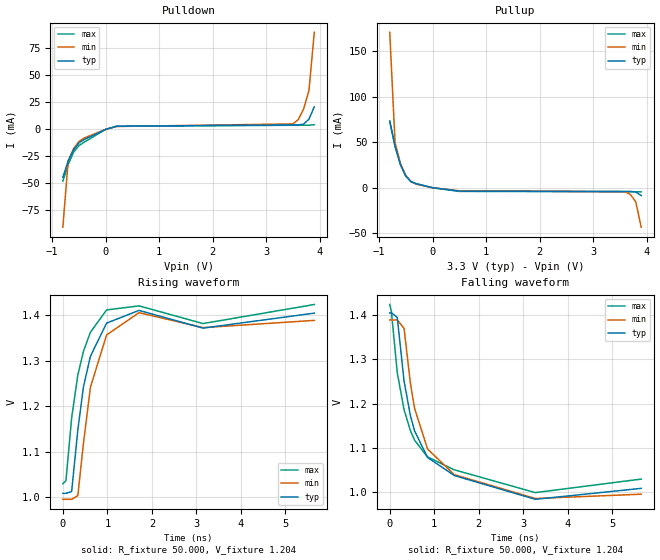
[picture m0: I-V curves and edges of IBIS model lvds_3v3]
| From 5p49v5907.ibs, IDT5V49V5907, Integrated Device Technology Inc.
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[Model]   lvds_3v3
Model_type   Output
Polarity   Non-Inverting
|   typ   min   max
C_comp   2pF   1.5pF   2.5pF
Vmeas = 1.204V
Rref = 50
Cref = 0
Vref = 1.204V
|   typ   min   max
[Voltage range]   3.3V   3.135V   3.465V
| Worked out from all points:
|   slope of the pulldown table from 0 to 0.495 V, typ, clamps not added: 133 ohm
|   slope of the pullup table from 0 to 0.495 V, typ, clamps not added: 133 ohm
|   rising waveform, R_fixture 50.000, V_fixture 1.204: 20-80 % time 395ps typ, 362ps min, 409ps max; typ from 1.01 V to 1.41 V
|   falling waveform, R_fixture 50.000, V_fixture 1.204: 20-80 % time 549ps typ, 612ps min, 518ps max; typ from 1.41 V to 1.01 V
[Pulldown]
|Voltage   I (typ)   I (min)   I (max)
|Note, modeling breaks down at 250mA and above.  This is well beyond the functional   |
|operating range of the device.  Should this scenario occur, catastrophic failure and   |
|possible damage to the device and/or board is of higher concern than the I-V curve   |
|behavior.  The IBIS checker will flag currents in excess of 10A with warnings.  Lines   |
|with currents in excess of 0.35 A have been commented out.  The points still remain|
|available to the user if the user desires to use them.   |
|-3.30000e+00   -4.02303e+02   -3.43850e+02   -5.00905e+02
|-3.20000e+00   -3.84985e+02   -3.29430e+02   -4.78763e+02
|-3.10000e+00   -3.67667e+02   -3.15011e+02   -4.56621e+02
|-3.00000e+00   -3.50348e+02   -3.00592e+02   -4.34479e+02
|-2.90000e+00   -3.33030e+02   -2.86172e+02   -4.12336e+02
|-2.80000e+00   -3.15711e+02   -2.71753e+02   -3.90194e+02
|-2.70000e+00   -2.98393e+02   -2.57334e+02   -3.68051e+02
|-2.60000e+00   -2.81074e+02   -2.42915e+02   -3.45909e+02
|-2.50000e+00   -2.63756e+02   -2.28496e+02   -3.23766e+02
|-2.40000e+00   -2.46438e+02   -2.14078e+02   -3.01624e+02
|-2.30000e+00   -2.29119e+02   -1.99659e+02   -2.79481e+02
|-2.20000e+00   -2.11801e+02   -1.85240e+02   -2.57338e+02
|-2.10000e+00   -1.94483e+02   -1.70822e+02   -2.35196e+02
|-2.00000e+00   -1.77165e+02   -1.56404e+02   -2.13053e+02
|-1.90000e+00   -1.59847e+02   -1.41986e+02   -1.90910e+02
|-1.80000e+00   -1.42529e+02   -1.27568e+02   -1.68767e+02
|-1.70000e+00   -1.25212e+02   -1.13151e+02   -1.46625e+02
|-1.60000e+00   -1.07894e+02   -9.87338e+01   -1.24482e+02
|-1.50000e+00   -9.05771e+01   -8.43169e+01   -1.02339e+02
|-1.40000e+00   -7.32599e+01   -6.99002e+01   -8.01956e+01
|-1.30000e+00   -5.59483e+01   -5.54897e+01   -5.80558e+01
|-1.20000e+00   -3.86499e+01   -4.10891e+01   -3.59351e+01
|-1.10000e+00   -2.13523e+01   -2.66893e+01   -1.38156e+01
|-1.00000e+00   -4.11121e+00   -1.22900e+01   -3.71206e-01
|-9.00000e-01   -1.58211e-01   -1.14673e+00   -6.56113e-02
-800mV    -44.24mA   -90.48mA   -47.8mA
-700mV    -29.1mA    -29.15mA   -32.67mA
-600mV    -19.04mA   -17.89mA   -21.04mA
-500mV    -12.59mA   -11.23mA   -15.1mA
-400mV    -9.416mA   -7.901mA   -11.79mA
0V        -2.25nA    -5.835nA   -3.544nA
200mV     2.91mA     2.696mA    2.857mA
3.5V      4.185mA    5.074mA    3.832mA
3.6V      4.214mA    9.033mA    3.833mA
3.7V      4.842mA    18.82mA    3.834mA
3.8V      9.453mA    36.03mA    3.847mA
3.9V      21mA       89.84mA    4.372mA
| 4.00000e+00   3.97396e-02   8.80969e-01   9.84668e-03
| 4.10000e+00   6.64583e-02   1.38742e+01   2.40960e-02
| 4.20000e+00   2.91501e-01   3.66036e+01   4.67415e-02
| 4.30000e+00   8.82312e+00   5.93342e+01   6.98070e-02
| 4.40000e+00   3.61237e+01   8.20660e+01   1.15745e-01
| 4.50000e+00   6.34271e+01   1.04799e+02   3.50693e+00
| 4.60000e+00   9.07318e+01   1.27533e+02   3.64347e+01
| 4.70000e+00   1.18038e+02   1.50268e+02   7.13476e+01
| 4.80000e+00   1.45345e+02   1.73004e+02   1.06262e+02
| 4.90000e+00   1.72653e+02   1.95742e+02   1.41178e+02
| 5.00000e+00   1.99963e+02   2.18480e+02   1.76095e+02
| 5.10000e+00   2.27274e+02   2.41219e+02   2.11014e+02
| 5.20000e+00   2.54586e+02   2.63959e+02   2.45934e+02
| 5.30000e+00   2.81899e+02   2.86701e+02   2.80855e+02
| 5.40000e+00   3.09214e+02   3.09443e+02   3.15777e+02
| 5.50000e+00   3.36529e+02   3.32186e+02   3.50701e+02
| 5.60000e+00   3.63845e+02   3.54931e+02   3.85627e+02
| 5.70000e+00   3.91163e+02   3.77676e+02   4.20553e+02
| 5.80000e+00   4.18481e+02   4.00423e+02   4.55481e+02
| 5.90000e+00   4.45801e+02   4.23170e+02   4.90409e+02
| 6.00000e+00   4.73122e+02   4.45919e+02   5.25339e+02
| 6.10000e+00   5.00444e+02   4.68669e+02   5.60270e+02
| 6.20000e+00   5.27767e+02   4.91419e+02   5.95202e+02
| 6.30000e+00   5.55091e+02   5.14172e+02   6.30136e+02
| 6.40000e+00   5.82417e+02   5.36925e+02   6.65070e+02
| 6.50000e+00   6.09743e+02   5.59680e+02   7.00006e+02
| 6.60000e+00   6.37071e+02   5.82436e+02   7.34943e+02
[Pullup]
|Voltage   I (typ)   I (min)   I (max)
|Note, modeling breaks down at 250mA and above.  This is well beyond the functional   |
|operating range of the device.  Should this scenario occur, catastrophic failure and   |
|possible damage to the device and/or board is of higher concern than the I-V curve   |
|behavior.  The IBIS checker will flag currents in excess of 10A with warnings.  Lines   |
|with currents in excess of 0.35 A have been commented out.  The points still remain|
|available to the user if the user desires to use them.   |
|-3.30000e+00   6.37090e+02   5.44906e+02   6.37091e+02
|-3.20000e+00   6.09762e+02   5.22151e+02   6.09763e+02
|-3.10000e+00   5.82435e+02   4.99398e+02   5.82436e+02
|-3.00000e+00   5.55110e+02   4.76647e+02   5.55110e+02
|-2.90000e+00   5.27785e+02   4.53896e+02   5.27786e+02
|-2.80000e+00   5.00462e+02   4.31147e+02   5.00463e+02
|-2.70000e+00   4.73140e+02   4.08399e+02   4.73141e+02
|-2.60000e+00   4.45819e+02   3.85652e+02   4.45819e+02
|-2.50000e+00   4.18499e+02   3.62906e+02   4.18499e+02
|-2.40000e+00   3.91180e+02   3.40161e+02   3.91180e+02
|-2.30000e+00   3.63862e+02   3.17417e+02   3.63863e+02
|-2.20000e+00   3.36545e+02   2.94674e+02   3.36546e+02
|-2.10000e+00   3.09229e+02   2.71931e+02   3.09230e+02
|-2.00000e+00   2.81915e+02   2.49190e+02   2.81915e+02
|-1.90000e+00   2.54601e+02   2.26450e+02   2.54601e+02
|-1.80000e+00   2.27288e+02   2.03711e+02   2.27289e+02
|-1.70000e+00   1.99977e+02   1.80973e+02   1.99977e+02
|-1.60000e+00   1.72667e+02   1.58236e+02   1.72667e+02
|-1.50000e+00   1.45358e+02   1.35500e+02   1.45358e+02
|-1.40000e+00   1.18050e+02   1.12765e+02   1.18050e+02
|-1.30000e+00   9.07429e+01   9.00309e+01   9.07432e+01
|-1.20000e+00   6.34374e+01   6.72980e+01   6.34377e+01
|-1.10000e+00   3.61332e+01   4.45663e+01   3.61334e+01
|-1.00000e+00   8.83172e+00   2.18357e+01   8.83194e+00
|-9.00000e-01   2.99168e-01   2.52120e+00   2.99347e-01
-800mV    73.09mA    170.8mA    73.28mA
-700mV    45.24mA    49.61mA    45.42mA
-600mV    25.45mA    26.63mA    25.6mA
-500mV    12.67mA    13.62mA    12.81mA
-400mV    6.575mA    6.566mA    6.688mA
-300mV    4.339mA    3.834mA    4.429mA
0V        154.1pA    2.459nA    164.7pA
500mV     -3.727mA   -3.409mA   -4.029mA
3.6V      -4.048mA   -4.394mA   -4.416mA
3.7V      -4.089mA   -7.527mA   -4.416mA
3.8V      -4.721mA   -15.63mA   -4.421mA
3.9V      -8.602mA   -43.34mA   -4.536mA
| 4.00000e+00   -1.80708e-02   -4.12742e-01   -5.88528e-03
| 4.10000e+00   -3.35072e-02   -7.23845e+00   -1.16434e-02
| 4.20000e+00   -1.46126e-01   -2.16361e+01   -2.30196e-02
| 4.30000e+00   -4.09665e+00   -3.60347e+01   -4.50229e-02
| 4.40000e+00   -2.13358e+01   -5.04338e+01   -4.19750e-01
| 4.50000e+00   -3.86320e+01   -6.48381e+01   -1.00943e+01
| 4.60000e+00   -5.59293e+01   -7.92538e+01   -2.73898e+01
| 4.70000e+00   -7.32398e+01   -9.36699e+01   -4.46863e+01
| 4.80000e+00   -9.05561e+01   -1.08086e+02   -6.19856e+01
| 4.90000e+00   -1.07873e+02   -1.22503e+02   -7.93010e+01
| 5.00000e+00   -1.25189e+02   -1.36920e+02   -9.66174e+01
| 5.10000e+00   -1.42506e+02   -1.51337e+02   -1.13934e+02
| 5.20000e+00   -1.59824e+02   -1.65755e+02   -1.31251e+02
| 5.30000e+00   -1.77141e+02   -1.80173e+02   -1.48568e+02
| 5.40000e+00   -1.94458e+02   -1.94591e+02   -1.65885e+02
| 5.50000e+00   -2.11776e+02   -2.09009e+02   -1.83203e+02
| 5.60000e+00   -2.29094e+02   -2.23427e+02   -2.00520e+02
| 5.70000e+00   -2.46412e+02   -2.37846e+02   -2.17838e+02
| 5.80000e+00   -2.63730e+02   -2.52264e+02   -2.35156e+02
| 5.90000e+00   -2.81048e+02   -2.66683e+02   -2.52474e+02
| 6.00000e+00   -2.98367e+02   -2.81102e+02   -2.69792e+02
| 6.10000e+00   -3.15685e+02   -2.95521e+02   -2.87110e+02
| 6.20000e+00   -3.33003e+02   -3.09940e+02   -3.04429e+02
| 6.30000e+00   -3.50321e+02   -3.24360e+02   -3.21747e+02
| 6.40000e+00   -3.67640e+02   -3.38779e+02   -3.39065e+02
| 6.50000e+00   -3.84958e+02   -3.53198e+02   -3.56384e+02
| 6.60000e+00   -4.02277e+02   -3.67618e+02   -3.73702e+02
[Ramp]
|   typ   min   max
dV/dt_r   0.241/0.409n   0.239/0.406n   0.242/0.414n
dV/dt_f   0.239/0.726n   0.238/0.753n   0.24/0.705n
R_load =   50
[Rising Waveform]
R_fixture = 50.000
V_fixture = 1.204
V_fixture_min = 1.204
V_fixture_max = 1.204
C_fixture = 0.000
|  time   V(typ)   V(min)   V(max)
0s        1.008V     994.8mV    1.029V
69.8ps    1.008V     994.8mV    1.036V
197.3ps   1.012V     994.8mV    1.174V
336.8ps   1.148V     1.003V     1.269V
463.2ps   1.243V     1.119V     1.321V
619.5ps   1.31V      1.242V     1.363V
982.5ps   1.383V     1.357V     1.412V
1.71ns    1.411V     1.406V     1.421V
3.148ns   1.372V     1.373V     1.382V
5.647ns   1.405V     1.389V     1.424V
[Falling Waveform]
R_fixture = 50.000
V_fixture = 1.204
V_fixture_min = 1.204
V_fixture_max = 1.204
C_fixture = 0.000
|  time   V(typ)   V(min)   V(max)
0s        1.405V     1.389V     1.424V
37.87ps   1.405V     1.389V     1.408V
169ps     1.395V     1.389V     1.27V
321.7ps   1.251V     1.37V      1.186V
463.2ps   1.173V     1.247V     1.139V
557.8ps   1.138V     1.189V     1.117V
849.6ps   1.078V     1.097V     1.079V
1.45ns    1.037V     1.039V     1.05V
3.27ns    983.2mV    985.1mV    998.4mV
5.647ns   1.008V     994.8mV    1.029V
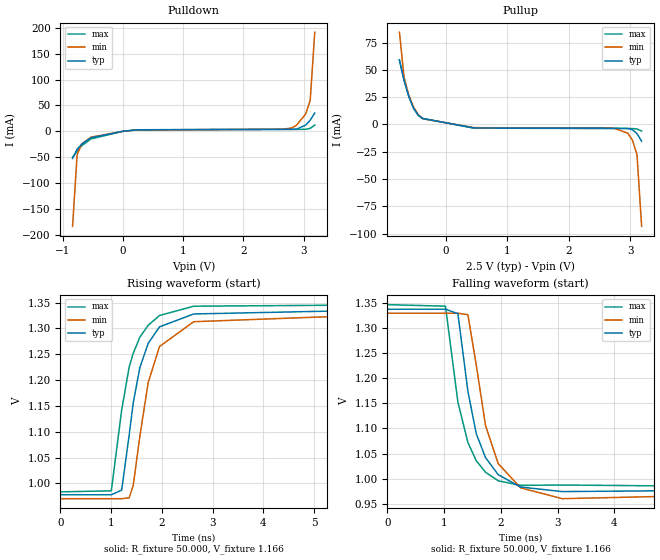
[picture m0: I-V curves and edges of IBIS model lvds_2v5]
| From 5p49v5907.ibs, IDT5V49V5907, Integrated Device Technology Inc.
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[Model]   lvds_2v5
Model_type   Output
Polarity   Non-Inverting
|   typ   min   max
C_comp   2pF   1.5pF   2.5pF
Vmeas = 1.161V
Rref = 50
Cref = 0
Vref = 1.161V
|   typ   min   max
[Voltage range]   2.5V   2.375V   2.625V
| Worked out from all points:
|   slope of the pulldown table from 0 to 0.375 V, typ, clamps not added: 109 ohm
|   slope of the pullup table from 0 to 0.375 V, typ, clamps not added: 128 ohm
|   rising waveform, R_fixture 50.000, V_fixture 1.166: 20-80 % time 398ps typ, 417ps min, 404ps max; typ from 0.978 V to 1.34 V
|   falling waveform, R_fixture 50.000, V_fixture 1.166: 20-80 % time 373ps typ, 372ps min, 358ps max; typ from 1.34 V to 0.978 V
[Pulldown]
|Voltage   I (typ)   I (min)   I (max)
|Note, modeling breaks down at 250mA and above.  This is well beyond the functional   |
|operating range of the device.  Should this scenario occur, catastrophic failure and   |
|possible damage to the device and/or board is of higher concern than the I-V curve   |
|behavior.  The IBIS checker will flag currents in excess of 10A with warnings.  Lines   |
|with currents in excess of 0.35 A have been commented out.  The points still remain|
|available to the user if the user desires to use them.   |
|-2.50000e+00   -2.63748e+02   -2.28489e+02   -3.23757e+02
|-2.42424e+00   -2.50628e+02   -2.17566e+02   -3.06982e+02
|-2.34848e+00   -2.37509e+02   -2.06643e+02   -2.90208e+02
|-2.27273e+00   -2.24389e+02   -1.95720e+02   -2.73434e+02
|-2.19697e+00   -2.11269e+02   -1.84797e+02   -2.56659e+02
|-2.12121e+00   -1.98150e+02   -1.73874e+02   -2.39885e+02
|-2.04545e+00   -1.85030e+02   -1.62952e+02   -2.23110e+02
|-1.96970e+00   -1.71911e+02   -1.52029e+02   -2.06336e+02
|-1.89394e+00   -1.58792e+02   -1.41107e+02   -1.89561e+02
|-1.81818e+00   -1.45672e+02   -1.30185e+02   -1.72787e+02
|-1.74242e+00   -1.32553e+02   -1.19262e+02   -1.56012e+02
|-1.66667e+00   -1.19434e+02   -1.08340e+02   -1.39238e+02
|-1.59091e+00   -1.06315e+02   -9.74186e+01   -1.22463e+02
|-1.51515e+00   -9.31963e+01   -8.64969e+01   -1.05689e+02
|-1.43939e+00   -8.00775e+01   -7.55754e+01   -8.89138e+01
|-1.36364e+00   -6.69587e+01   -6.46541e+01   -7.21388e+01
|-1.28788e+00   -5.38477e+01   -5.37405e+01   -5.53700e+01
|-1.21212e+00   -4.07432e+01   -4.28313e+01   -3.86124e+01
|-1.13636e+00   -2.76391e+01   -3.19225e+01   -2.18553e+01
|-1.06061e+00   -1.45353e+01   -2.10140e+01   -5.09928e+00
|-9.84848e-01   -2.38189e+00   -1.01058e+01   -2.16735e-01
|-9.09091e-01   -1.97810e-01   -1.49623e+00   -6.53950e-02
-833.3mV  -52.51mA   -184mA     -50.21mA
-757.6mV  -34.52mA   -45.62mA   -38.6mA
-681.8mV  -25.03mA   -24.44mA   -27.97mA
-530.3mV  -12.59mA   -11.42mA   -14.84mA
0V        -204pA     -4.142nA   -203.1pA
227.3mV   2.879mA    2.591mA    2.982mA
2.652V    3.845mA    4.04mA     3.665mA
2.803V    3.877mA    6.543mA    3.666mA
2.879V    4.205mA    11.68mA    3.667mA
3.03V     11.84mA    33.41mA    3.859mA
3.106V    21.57mA    59.45mA    5.697mA
3.182V    35.42mA    191.8mA    12.01mA
| 3.25758e+00   5.32977e-02   1.48189e+00   2.34460e-02
| 3.33333e+00   8.43129e-02   1.23584e+01   3.98133e-02
| 3.40909e+00   3.79870e-01   2.95775e+01   5.87067e-02
| 3.48485e+00   5.36691e+00   4.67972e+01   7.48224e-02
| 3.56061e+00   2.53677e+01   6.40176e+01   1.16362e-01
| 3.63636e+00   4.60515e+01   8.12387e+01   1.18523e+00
| 3.71212e+00   6.67361e+01   9.84604e+01   1.97190e+01
| 3.78788e+00   8.74214e+01   1.15683e+02   4.61674e+01
| 3.86364e+00   1.08108e+02   1.32906e+02   7.26167e+01
| 3.93939e+00   1.28794e+02   1.50130e+02   9.90669e+01
| 4.01515e+00   1.49482e+02   1.67354e+02   1.25518e+02
| 4.09091e+00   1.70170e+02   1.84579e+02   1.51970e+02
| 4.16667e+00   1.90859e+02   2.01804e+02   1.78422e+02
| 4.24242e+00   2.11548e+02   2.19030e+02   2.04876e+02
| 4.31818e+00   2.32239e+02   2.36257e+02   2.31330e+02
| 4.39394e+00   2.52930e+02   2.53484e+02   2.57785e+02
| 4.46970e+00   2.73621e+02   2.70712e+02   2.84240e+02
| 4.54545e+00   2.94314e+02   2.87940e+02   3.10697e+02
| 4.62121e+00   3.15006e+02   3.05169e+02   3.37154e+02
| 4.69697e+00   3.35700e+02   3.22398e+02   3.63612e+02
| 4.77273e+00   3.56394e+02   3.39629e+02   3.90070e+02
| 4.84848e+00   3.77089e+02   3.56859e+02   4.16530e+02
| 4.92424e+00   3.97784e+02   3.74091e+02   4.42990e+02
| 5.00000e+00   4.18480e+02   3.91322e+02   4.69450e+02
[Pullup]
|Voltage   I (typ)   I (min)   I (max)
|Note, modeling breaks down at 250mA and above.  This is well beyond the functional   |
|operating range of the device.  Should this scenario occur, catastrophic failure and   |
|possible damage to the device and/or board is of higher concern than the I-V curve   |
|behavior.  The IBIS checker will flag currents in excess of 10A with warnings.  Lines   |
|with currents in excess of 0.35 A have been commented out.  The points still remain|
|available to the user if the user desires to use them.   |
|-2.50000e+00   4.18495e+02   3.62903e+02   4.18496e+02
|-2.42424e+00   3.97799e+02   3.45672e+02   3.97800e+02
|-2.34848e+00   3.77104e+02   3.28441e+02   3.77104e+02
|-2.27273e+00   3.56409e+02   3.11211e+02   3.56409e+02
|-2.19697e+00   3.35715e+02   2.93982e+02   3.35715e+02
|-2.12121e+00   3.15021e+02   2.76753e+02   3.15021e+02
|-2.04545e+00   2.94328e+02   2.59525e+02   2.94328e+02
|-1.96970e+00   2.73635e+02   2.42297e+02   2.73636e+02
|-1.89394e+00   2.52943e+02   2.25070e+02   2.52944e+02
|-1.81818e+00   2.32252e+02   2.07843e+02   2.32252e+02
|-1.74242e+00   2.11561e+02   1.90618e+02   2.11562e+02
|-1.66667e+00   1.90871e+02   1.73392e+02   1.90872e+02
|-1.59091e+00   1.70182e+02   1.56167e+02   1.70182e+02
|-1.51515e+00   1.49493e+02   1.38943e+02   1.49494e+02
|-1.43939e+00   1.28805e+02   1.21719e+02   1.28806e+02
|-1.36364e+00   1.08118e+02   1.04496e+02   1.08119e+02
|-1.28788e+00   8.74315e+01   8.72739e+01   8.74319e+01
|-1.21212e+00   6.67456e+01   7.00521e+01   6.67460e+01
|-1.13636e+00   4.60605e+01   5.28310e+01   4.60608e+01
|-1.06061e+00   2.53760e+01   3.56105e+01   2.53763e+01
|-9.84848e-01   5.37465e+00   1.83907e+01   5.37492e+00
|-9.09091e-01   3.86946e-01   3.33101e+00   3.87187e-01
|-8.33333e-01   9.07404e-02   3.69532e-01   9.09591e-02
-757.6mV  58.9mA     84.47mA    59.12mA
-681.8mV  40.26mA    43.08mA    40.47mA
-606.1mV  25.66mA    26.93mA    25.85mA
-530.3mV  15.1mA     16.26mA    15.28mA
-454.5mV  8.518mA    9.159mA    8.67mA
-378.8mV  5.408mA    5.259mA    5.539mA
454.5mV   -3.167mA   -2.923mA   -3.387mA
2.727V    -3.45mA    -3.348mA   -3.732mA
2.955V    -3.657mA   -7.921mA   -3.737mA
3.03V     -4.782mA   -14.09mA   -3.782mA
3.106V    -8.414mA   -27.47mA   -4.154mA
3.182V    -15.33mA   -93.33mA   -5.978mA
| 3.25758e+00   -2.52492e-02   -6.81188e-01   -1.07478e-02
| 3.33333e+00   -4.29597e-02   -6.27801e+00   -1.87686e-02
| 3.40909e+00   -1.87084e-01   -1.71851e+01   -2.98709e-02
| 3.48485e+00   -2.36949e+00   -2.80928e+01   -6.11800e-02
| 3.56061e+00   -1.45216e+01   -3.90009e+01   -4.27196e-01
| 3.63636e+00   -2.76244e+01   -4.99093e+01   -6.00560e+00
| 3.71212e+00   -4.07276e+01   -6.08196e+01   -1.91078e+01
| 3.78788e+00   -5.38315e+01   -7.17390e+01   -3.22108e+01
| 3.86364e+00   -6.69419e+01   -8.26600e+01   -4.53142e+01
| 3.93939e+00   -8.00602e+01   -9.35812e+01   -5.84188e+01
| 4.01515e+00   -9.31786e+01   -1.04503e+02   -7.15337e+01
| 4.09091e+00   -1.06297e+02   -1.15424e+02   -8.46520e+01
| 4.16667e+00   -1.19416e+02   -1.26346e+02   -9.77704e+01
| 4.24242e+00   -1.32534e+02   -1.37268e+02   -1.10889e+02
| 4.31818e+00   -1.45653e+02   -1.48190e+02   -1.24008e+02
| 4.39394e+00   -1.58772e+02   -1.59112e+02   -1.37126e+02
| 4.46970e+00   -1.71891e+02   -1.70035e+02   -1.50245e+02
| 4.54545e+00   -1.85011e+02   -1.80957e+02   -1.63364e+02
| 4.62121e+00   -1.98130e+02   -1.91880e+02   -1.76484e+02
| 4.69697e+00   -2.11249e+02   -2.02803e+02   -1.89603e+02
| 4.77273e+00   -2.24369e+02   -2.13725e+02   -2.02722e+02
| 4.84848e+00   -2.37488e+02   -2.24648e+02   -2.15842e+02
| 4.92424e+00   -2.50608e+02   -2.35571e+02   -2.28961e+02
| 5.00000e+00   -2.63728e+02   -2.46495e+02   -2.42081e+02
[Ramp]
|   typ   min   max
dV/dt_r   0.21/0.413n   0.212/0.419n   0.209/0.425n
dV/dt_f   0.21/0.384n   0.212/0.413n   0.207/0.364n
R_load =   50
[Rising Waveform]
R_fixture = 50.000
V_fixture = 1.166
V_fixture_min = 1.166
V_fixture_max = 1.161
C_fixture = 0.000
|  time   V(typ)   V(min)   V(max)
0s        978mV      970.4mV    983.6mV
1.003ns   978mV      970.4mV    985.6mV
1.207ns   986.9mV    970.4mV    1.142V
1.354ns   1.093V     972mV      1.225V
1.435ns   1.156V     996.2mV    1.252V
1.565ns   1.224V     1.091V     1.283V
1.729ns   1.271V     1.195V     1.306V
1.953ns   1.303V     1.265V     1.325V
2.626ns   1.328V     1.313V     1.343V
7ns       1.337V     1.329V     1.346V
[Falling Waveform]
R_fixture = 50.000
V_fixture = 1.166
V_fixture_min = 1.166
V_fixture_max = 1.161
C_fixture = 0.000
|  time   V(typ)   V(min)   V(max)
0s        1.337V     1.329V     1.346V
1.024ns   1.337V     1.329V     1.343V
1.243ns   1.328V     1.329V     1.152V
1.419ns   1.174V     1.326V     1.072V
1.565ns   1.09V      1.227V     1.036V
1.729ns   1.042V     1.106V     1.013V
1.953ns   1.008V     1.03V      995.9mV
2.346ns   983.5mV    981.9mV    986.8mV
3.081ns   974.4mV    960.3mV    987.5mV
7ns       978mV      970.4mV    983.6mV
